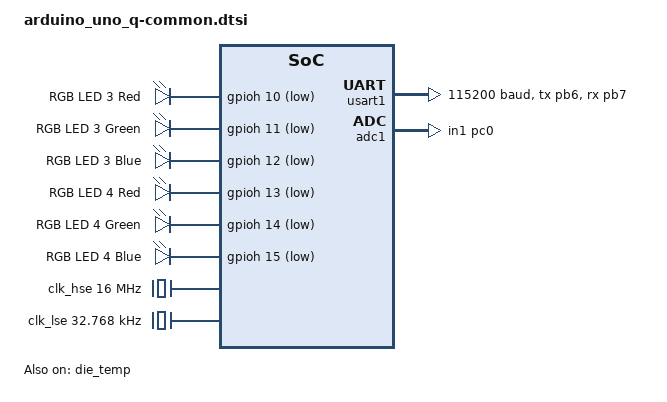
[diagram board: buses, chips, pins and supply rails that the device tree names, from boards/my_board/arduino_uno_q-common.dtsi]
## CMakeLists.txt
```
cmake_minimum_required(VERSION 3.20.0)

list(APPEND DTS_ROOT ${CMAKE_CURRENT_SOURCE_DIR}/..)
find_package(Zephyr REQUIRED)
project(my_zephyr_app)

target_sources(app PRIVATE src/main.cpp)
add_subdirectory(drivers/our_driver)
```

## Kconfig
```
menuconfig LED_SUBSYSTEM
    bool "LED Subsystem"

    if LED_SUBSYSTEM

        choice
            prompt "LED blink sleep time"
            default BLINK_SLEEP_500MS
            config BLINK_SLEEP_100MS
                bool "Fast (100ms)"
            config BLINK_SLEEP_500MS
                bool "Medium (500ms)"
            config BLINK_SLEEP_2000MS
                bool "Slow (2s)"
        endchoice

        config APP_HEARTBEAT_PERIOD_MS
            int
            range 100 2000
            default 500 if BLINK_SLEEP_500MS
            default 100 if BLINK_SLEEP_100MS
            default 2000 if BLINK_SLEEP_2000MS
            default 500

        menuconfig LED_ADVANCED
            bool "Advanced LED settings"
            if LED_ADVANCED
                config LED_BRIGHTNESS
                    int "LED brightness (0-100)"
                    default 100
                    range 0 100
                config LED_FADE_DURATION_MS
                    int "Fade duration (ms)"
                    default 500
                    range 0 5000
            endif
        menu "Expert settings"
            visible if LED_ADVANCED
            config LED_DEBUG
                bool "Enable LED debugging"
            config CUSTOM_BLINK_PATTERN
                bool "Custom blink pattern"

endmenu

endif   # LED_SUBSYSTEM

source "Kconfig.zephyr"
rsource "drivers/our_driver/Kconfig"
```

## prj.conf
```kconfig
CONFIG_GPIO=y
CONFIG_LOG=y
CONFIG_DEBUG_OPTIMIZATIONS=y

CONFIG_LED_SUBSYSTEM=y

CONFIG_SENSOR=y
CONFIG_OUR_DRIVER=y
```

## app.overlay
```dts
/ {
    /* Send console/logs to lpuart1, which is wired to the Linux side (/dev/ttyHS1) */
    chosen {
        zephyr,console = &lpuart1;
        zephyr,shell-uart = &lpuart1;
    };

    aliases {
        app-led = &led3_red;
    };

    our_driver0: our_driver {
        compatible = "our,driver";
        status = "okay";
        led-gpios = <&gpioh 14 GPIO_ACTIVE_LOW>; /* RGB LED 4 Green */
    };
    our_driver1: our_driver1 {
        compatible = "our,driver";
        status = "okay";
        led-gpios = <&gpioh 15 GPIO_ACTIVE_LOW>; /* RGB LED 4 Blue */
    };
};
```

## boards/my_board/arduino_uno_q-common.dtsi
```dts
/*
 * Copyright (c) 2021 Linaro Limited
 * Copyright (c) 2024 STMicroelectronics
 * Copyright (c) 2025 Arduino SA
 *
 * SPDX-License-Identifier: Apache-2.0
 */

#include <zephyr/dt-bindings/gpio/gpio.h>

/ {

	leds {
		compatible = "gpio-leds";

		led3_red: led3_red {
			gpios = <&gpioh 10 GPIO_ACTIVE_LOW>;
			label = "RGB LED 3 Red";
		};

		led3_green: led3_green {
			gpios = <&gpioh 11 GPIO_ACTIVE_LOW>;
			label = "RGB LED 3 Green";
		};

		led3_blue: led3_blue {
			gpios = <&gpioh 12 GPIO_ACTIVE_LOW>;
			label = "RGB LED 3 Blue";
		};

		led4_red: led4_red {
			gpios = <&gpioh 13 GPIO_ACTIVE_LOW>;
			label = "RGB LED 4 Red";
		};

		led4_green: led4_green {
			gpios = <&gpioh 14 GPIO_ACTIVE_LOW>;
			label = "RGB LED 4 Green";
		};

		led4_blue: led4_blue {
			gpios = <&gpioh 15 GPIO_ACTIVE_LOW>;
			label = "RGB LED 4 Blue";
		};
	};
};

&clk_hsi48 {
	status = "okay";
};

&clk_hse {
	clock-frequency = <DT_FREQ_M(16)>;
	status = "okay";
};

&clk_lse {
	clock-frequency = <32768>;
	status = "okay";
};

&clk_msis {
	status = "okay";
	msi-range = <4>;
	msi-pll-mode;
};

&pll1 {
	div-m = <1>;
	mul-n = <80>;
	div-q = <2>;
	div-r = <2>;
	clocks = <&clk_msis>;
	status = "okay";
};

&rcc {
	clocks = <&pll1>;
	clock-frequency = <DT_FREQ_M(160)>;
	ahb-prescaler = <1>;
	apb1-prescaler = <1>;
	apb2-prescaler = <1>;
	apb3-prescaler = <1>;
};

&usart1 {
	pinctrl-0 = <&usart1_tx_pb6 &usart1_rx_pb7>;
	pinctrl-names = "default";
	current-speed = <115200>;
	status = "okay";
};

&adc1 {
	pinctrl-0 = <&adc1_in1_pc0>;
	pinctrl-names = "default";
};

&die_temp {
	status = "okay";
};

&gpioh {
	status = "okay";
};
```

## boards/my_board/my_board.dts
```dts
/dts-v1/;
#include <st/u5/stm32u585Xi.dtsi>
#include <st/u5/stm32u585aiixq-pinctrl.dtsi>
#include "arduino_uno_q-common.dtsi"
#include <zephyr/dt-bindings/memory-attr/memory-attr.h>
#include <zephyr/dt-bindings/memory-attr/memory-attr-arm.h>
/ {
	model = "My Board";
	compatible = "arduino,uno_q";

	chosen {
		zephyr,console = &usart1;
		zephyr,shell-uart = &usart1;
		zephyr,sram = &sram0;
		zephyr,flash = &flash0;
		zephyr,code-partition = &slot0_partition;
	};

	aliases {
		led0 = &led3_green;
		led1 = &led3_red;
		die-temp0 = &die_temp;
	};
};

&flash0 {
	partitions {
		ranges;
		#address-cells = <1>;
		#size-cells = <1>;

		/*
		 * Following flash partition is dedicated to the use of stm32u585
		 * with TZEN=0 (so w/o TFM).
		 * Set the partitions with first MB to make use of the whole Bank1
		 */
		boot_partition: partition@0 {
			compatible = "zephyr,mapped-partition";
			label = "mcuboot";
			reg = <0x00000000 DT_SIZE_K(64)>;
		};

		slot0_partition: partition@10000 {
			compatible = "zephyr,mapped-partition";
			label = "image-0";
			reg = <0x00010000 DT_SIZE_K(416)>;
		};

		slot1_partition: partition@78000 {
			compatible = "zephyr,mapped-partition";
			label = "image-1";
			reg = <0x00078000 DT_SIZE_K(416)>;
		};

		storage_partition: partition@e0000 {
			compatible = "zephyr,mapped-partition";
			label = "storage";
			reg = <0x000e0000 DT_SIZE_K(128)>;
		};
	};
};

&gpdma1 {
	status = "okay";
};

&adc1 {
	st,adc-prescaler = <4>;
	status = "okay";
};
```

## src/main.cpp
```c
#include <zephyr/drivers/gpio.h>
#include <zephyr/drivers/sensor.h>
#include <zephyr/kernel.h>
#include <zephyr/logging/log.h>

#include "our_driver.h"

/* The devicetree node identifiers for the aliases */
#define LED_NODE_RED DT_ALIAS(app_led)
#define LED_NODE_BLUE DT_ALIAS(led1)

static const struct gpio_dt_spec led_red = GPIO_DT_SPEC_GET(LED_NODE_RED, gpios);
static const struct gpio_dt_spec led_blue = GPIO_DT_SPEC_GET(LED_NODE_BLUE, gpios);

LOG_MODULE_REGISTER(main, LOG_LEVEL_INF);

namespace {
    // Test my driver
    void test() {
        const struct device* driver = DEVICE_DT_GET(DT_NODELABEL(our_driver0));
        struct sensor_value value;

        // Extension API: change a field in the instance's dynamic data
        our_driver_set_level(driver, 42);

        // Calls sample_fetch_my_impl(driver, SENSOR_CHAN_ALL) -> LED ON
        auto ret = sensor_sample_fetch(driver);
        LOG_INF("Sample fetch returned: %d", ret);
        k_msleep(5000);

        // Calls channel_get_my_impl(driver, SENSOR_CHAN_AMBIENT_TEMP, &value) -> LED OFF
        ret = sensor_channel_get(driver, SENSOR_CHAN_AMBIENT_TEMP, &value);
        LOG_INF("Channel get returned: %d, led: %d, level: %d", ret, value.val1, value.val2);
    }
}

int main(void)
{
    test();
    bool is_red_turn = true;

    /* Check if devices are ready */
    if (!gpio_is_ready_dt(&led_red)) {
        LOG_ERR("Red LED device not ready");
        return 0;
    }
    if (!gpio_is_ready_dt(&led_blue)) {
        LOG_ERR("Blue LED device not ready");
        return 0;
    }

    /* Configure both as outputs, initially OFF (INACTIVE) */
    if (gpio_pin_configure_dt(&led_red, GPIO_OUTPUT_INACTIVE) < 0) return 0;
    if (gpio_pin_configure_dt(&led_blue, GPIO_OUTPUT_INACTIVE) < 0) return 0;

    LOG_INF("Starting alternating blink loop...");

    while (1) {
        if (is_red_turn) {
            /* Set Red ACTIVE (1) and Blue INACTIVE (0) */
            gpio_pin_set_dt(&led_red, 1);
            gpio_pin_set_dt(&led_blue, 0);
            LOG_INF("LED state: RED is ON, BLUE is OFF");
        } else {
            /* Set Red INACTIVE (0) and Blue ACTIVE (1) */
            gpio_pin_set_dt(&led_red, 0);
            gpio_pin_set_dt(&led_blue, 1);
            LOG_INF("LED state: RED is OFF, BLUE is ON");
        }

        /* Swap turns for the next loop iteration */
        is_red_turn = !is_red_turn;
        
        k_msleep(CONFIG_APP_HEARTBEAT_PERIOD_MS);
    }
    return 0;
}
```
